# INV_X1.full.lef
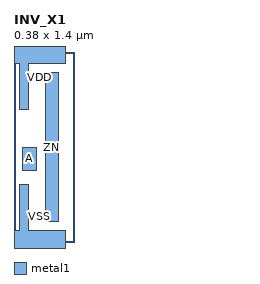
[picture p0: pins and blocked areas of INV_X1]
MACRO INV_X1
  CLASS core ;
  FOREIGN INV_X1 0.0 0.0 ;
  ORIGIN 0 0 ;
  SYMMETRY X Y ;
  SITE FreePDK45_38x28_10R_NP_162NW_34O ;
  SIZE 0.38 BY 1.4 ;
  PIN A
    DIRECTION INPUT ;
    ANTENNAPARTIALMETALAREA 0.018375 LAYER metal1 ;
    ANTENNAPARTIALMETALSIDEAREA 0.0728 LAYER metal1 ;
    ANTENNAGATEAREA 0.05225 ;
    PORT
      LAYER metal1 ;
        POLYGON 0.06 0.525 0.165 0.525 0.165 0.7 0.06 0.7  ;
    END
  END A
  PIN ZN
    DIRECTION OUTPUT ;
    ANTENNAPARTIALMETALAREA 0.1045 LAYER metal1 ;
    ANTENNAPARTIALMETALSIDEAREA 0.3107 LAYER metal1 ;
    ANTENNADIFFAREA 0.109725 ;
    PORT
      LAYER metal1 ;
        POLYGON 0.23 0.15 0.325 0.15 0.325 1.25 0.23 1.25  ;
    END
  END ZN
  PIN VDD
    DIRECTION INOUT ;
    USE power ;
    SHAPE ABUTMENT ;
    PORT
      LAYER metal1 ;
        POLYGON 0 1.315 0.04 1.315 0.04 0.975 0.11 0.975 0.11 1.315 0.38 1.315 0.38 1.485 0 1.485  ;
    END
  END VDD
  PIN VSS
    DIRECTION INOUT ;
    USE ground ;
    SHAPE ABUTMENT ;
    PORT
      LAYER metal1 ;
        POLYGON 0 -0.085 0.38 -0.085 0.38 0.085 0.11 0.085 0.11 0.425 0.04 0.425 0.04 0.085 0 0.085  ;
    END
  END VSS
END INV_X1
